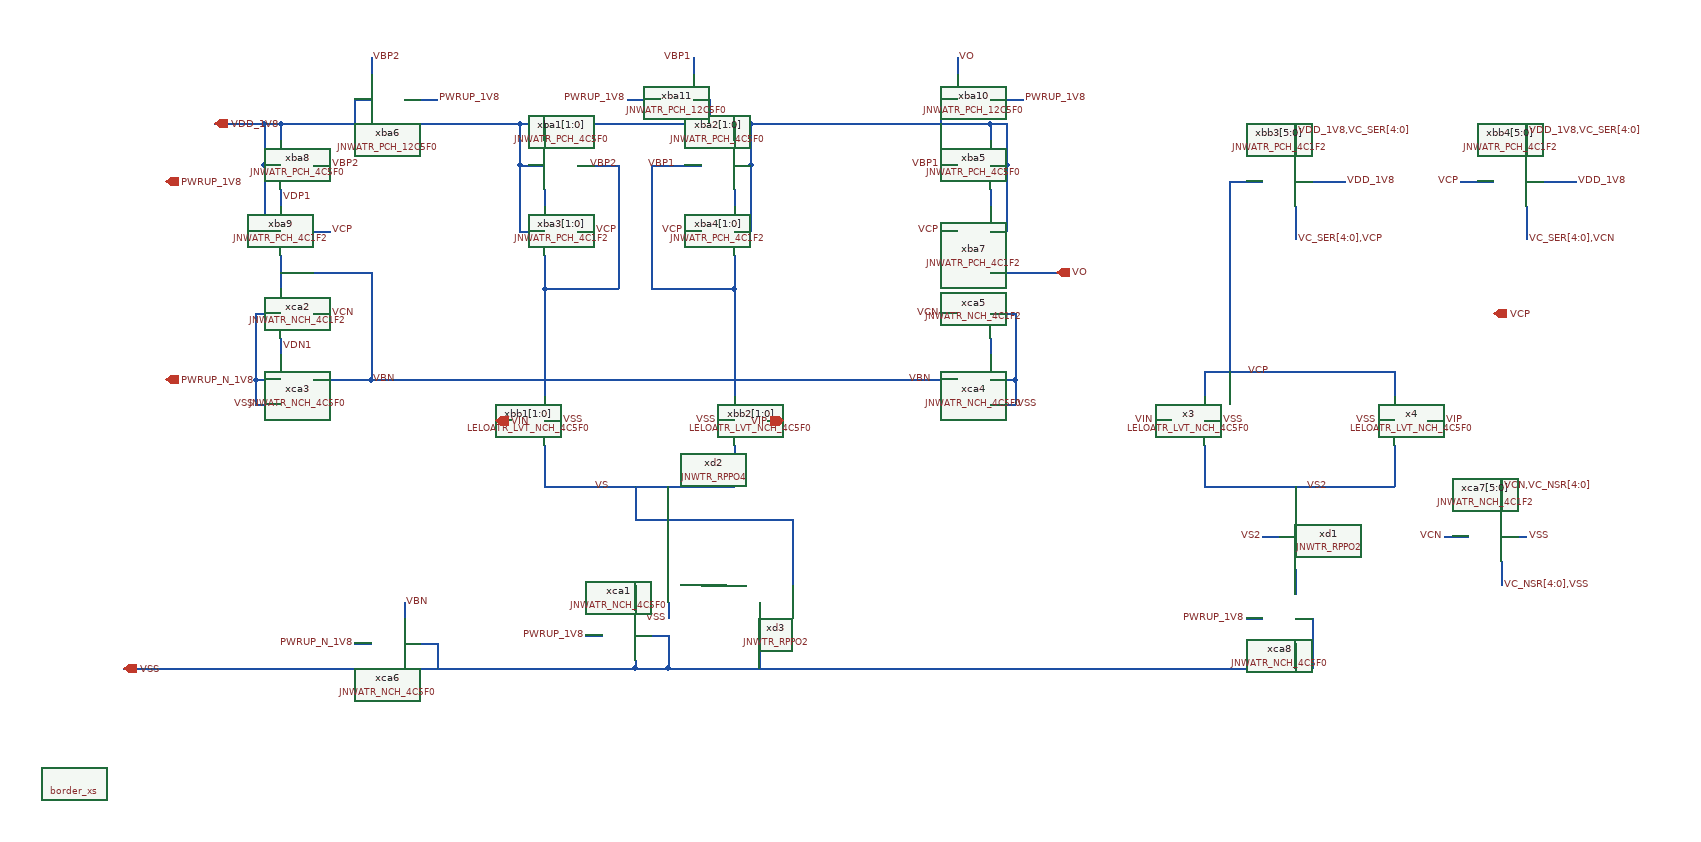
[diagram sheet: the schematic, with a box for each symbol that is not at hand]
v {xschem version=3.4.7 file_version=1.2}
G {}
K {}
V {}
S {}
E {}
N 100 -100 210 -100 {lab=VSS}
N 210 -760 270 -760 {lab=VDD_1V8}
N 610 -370 610 -320 {lab=VS}
N 610 -320 840 -320 {lab=VS}
N 840 -370 840 -320 {lab=VS}
N 760 -180 760 -160 {lab=VSS}
N 720 -320 720 -280 {lab=VS}
N 210 -100 720 -100 {lab=VSS}
N 720 -110 720 -100 {lab=VSS}
N 720 -140 760 -140 {lab=VSS}
N 760 -140 760 -100 {lab=VSS}
N 720 -100 760 -100 {lab=VSS}
N 720 -200 720 -170 {lab=#net1}
N 610 -400 630 -400 {lab=VSS}
N 820 -400 840 -400 {lab=VSS}
N 1410 -370 1410 -320 {lab=VS2}
N 1410 -320 1640 -320 {lab=VS2}
N 1640 -370 1640 -320 {lab=VS2}
N 1410 -400 1430 -400 {lab=VSS}
N 1620 -400 1640 -400 {lab=VSS}
N 580 -710 610 -710 {lab=VDD_1V8}
N 580 -760 580 -710 {lab=VDD_1V8}
N 580 -760 860 -760 {lab=VDD_1V8}
N 860 -760 860 -710 {lab=VDD_1V8}
N 840 -710 860 -710 {lab=VDD_1V8}
N 840 -760 840 -740 {lab=VDD_1V8}
N 610 -760 610 -740 {lab=VDD_1V8}
N 840 -630 860 -630 {lab=VDD_1V8}
N 860 -710 860 -630 {lab=VDD_1V8}
N 840 -680 840 -660 {lab=#net2}
N 650 -710 700 -710 {lab=VBP2}
N 700 -710 700 -560 {lab=VBP2}
N 610 -560 700 -560 {lab=VBP2}
N 610 -590 610 -560 {lab=VBP2}
N 610 -560 610 -430 {lab=VBP2}
N 740 -710 800 -710 {lab=VBP1}
N 740 -710 740 -560 {lab=VBP1}
N 740 -560 840 -560 {lab=VBP1}
N 840 -600 840 -560 {lab=VBP1}
N 610 -600 610 -590 {lab=VBP2}
N 580 -630 610 -630 {lab=VDD_1V8}
N 580 -710 580 -630 {lab=VDD_1V8}
N 840 -560 840 -430 {lab=VBP1}
N 1170 -760 1170 -710 {lab=VDD_1V8}
N 1150 -710 1170 -710 {lab=VDD_1V8}
N 1150 -760 1150 -740 {lab=VDD_1V8}
N 1150 -630 1170 -630 {lab=VDD_1V8}
N 1170 -710 1170 -630 {lab=VDD_1V8}
N 1150 -680 1150 -660 {lab=#net3}
N 1150 -600 1150 -560 {lab=VO}
N 650 -630 670 -630 {lab=VCP}
N 780 -630 800 -630 {lab=VCP}
N 610 -680 610 -660 {lab=#net4}
N 1090 -710 1110 -710 {lab=VBP1}
N 1090 -630 1110 -630 {lab=VCP}
N 860 -760 1150 -760 {lab=VDD_1V8}
N 1150 -760 1170 -760 {lab=VDD_1V8}
N 270 -760 270 -710 {lab=VDD_1V8}
N 270 -710 290 -710 {lab=VDD_1V8}
N 290 -760 290 -740 {lab=VDD_1V8}
N 270 -630 290 -630 {lab=VDD_1V8}
N 270 -710 270 -630 {lab=VDD_1V8}
N 290 -680 290 -660 {lab=VDP1}
N 290 -600 290 -560 {lab=VBN}
N 330 -710 350 -710 {lab=VBP2}
N 330 -630 350 -630 {lab=VCP}
N 290 -760 580 -760 {lab=VDD_1V8}
N 270 -760 290 -760 {lab=VDD_1V8}
N 290 -500 290 -480 {lab=VDN1}
N 260 -530 290 -530 {lab=VSS}
N 260 -530 260 -450 {lab=VSS}
N 260 -450 290 -450 {lab=VSS}
N 260 -450 260 -420 {lab=VSS}
N 260 -420 290 -420 {lab=VSS}
N 330 -530 350 -530 {lab=VCN}
N 330 -450 400 -450 {lab=VBN}
N 400 -580 400 -450 {lab=VBN}
N 290 -580 400 -580 {lab=VBN}
N 1150 -600 1150 -560 {lab=VO}
N 1150 -500 1150 -480 {lab=#net5}
N 1150 -530 1180 -530 {lab=VSS}
N 1180 -530 1180 -450 {lab=VSS}
N 1150 -450 1180 -450 {lab=VSS}
N 1180 -450 1180 -420 {lab=VSS}
N 1150 -420 1180 -420 {lab=VSS}
N 1090 -530 1110 -530 {lab=VCN}
N 1080 -450 1110 -450 {lab=VBN}
N 400 -450 1080 -450 {lab=VBN}
N 1150 -580 1230 -580 {lab=VO}
N 380 -790 400 -790 {lab=VDD_1V8}
N 380 -790 380 -760 {lab=VDD_1V8}
N 400 -840 400 -820 {lab=VBP2}
N 440 -790 480 -790 {lab=PWRUP_1V8}
N 790 -790 810 -790 {lab=VDD_1V8}
N 810 -790 810 -760 {lab=VDD_1V8}
N 790 -840 790 -820 {lab=VBP1}
N 710 -790 750 -790 {lab=PWRUP_1V8}
N 440 -130 480 -130 {lab=VSS}
N 480 -130 480 -100 {lab=VSS}
N 440 -180 440 -160 {lab=VBN}
N 380 -130 400 -130 {lab=PWRUP_N_1V8}
N 1410 -460 1410 -430 {lab=VCP}
N 1410 -460 1640 -460 {lab=VCP}
N 1640 -460 1640 -430 {lab=VCP}
N 880 -400 900 -400 {lab=VIP}
N 550 -400 570 -400 {lab=VIN}
N 1680 -400 1700 -400 {lab=VIP}
N 1350 -400 1370 -400 {lab=VIN}
N 1520 -690 1550 -690 {lab=VDD_1V8}
N 1550 -690 1580 -690 {lab=VDD_1V8}
N 1440 -690 1480 -690 {lab=VCP}
N 1520 -760 1520 -720 {lab=VDD_1V8,VC_SER[4:0]}
N 1520 -660 1520 -620 {lab=VC_SER[4:0],VCP}
N 1800 -690 1830 -690 {lab=VDD_1V8}
N 1830 -690 1860 -690 {lab=VDD_1V8}
N 1720 -690 1760 -690 {lab=VCP}
N 1800 -760 1800 -720 {lab=VDD_1V8,VC_SER[4:0]}
N 1800 -660 1800 -620 {lab=VC_SER[4:0],VCN}
N 1440 -690 1440 -460 {lab=VCP}
N 760 -100 1540 -100 {lab=VSS}
N 1540 -160 1540 -100 {lab=VSS}
N 1520 -160 1540 -160 {lab=VSS}
N 1520 -130 1520 -100 {lab=VSS}
N 1520 -220 1520 -190 {lab=#net6}
N 1480 -260 1500 -260 {lab=VS2}
N 1520 -320 1520 -300 {lab=VS2}
N 1460 -160 1480 -160 {lab=PWRUP_1V8}
N 1770 -330 1770 -290 {lab=VCN,VC_NSR[4:0]}
N 1700 -260 1730 -260 {lab=VCN}
N 1770 -260 1800 -260 {lab=VSS}
N 1770 -230 1770 -200 {lab=VC_NSR[4:0],VSS}
N 1090 -790 1110 -790 {lab=VDD_1V8}
N 1090 -790 1090 -760 {lab=VDD_1V8}
N 1110 -840 1110 -820 {lab=VO}
N 1150 -790 1190 -790 {lab=PWRUP_1V8}
N 660 -140 680 -140 {lab=PWRUP_1V8}
N 870 -180 870 -100 {lab=VSS}
N 800 -200 830 -200 {lab=#net7}
N 910 -280 910 -200 {lab=VS}
N 720 -280 910 -280 {lab=VS}
C {devices/ipin.sym} 210 -760 2 1 {name=p4 lab=VDD_1V8}
C {devices/ipin.sym} 100 -100 2 1 {name=p5 lab=VSS}
C {JNW_ATR_SKY130A/JNWATR_NCH_4C5F0.sym} 330 -450 0 1 {name=xca3}
C {devices/ipin.sym} 150 -450 2 1 {name=p9 lab=PWRUP_N_1V8}
C {devices/ipin.sym} 150 -690 2 1 {name=p10 lab=PWRUP_1V8}
C {cborder/border_xs.sym} 40 40 0 0 {user="Carsten Wulff" company="Carsten Wulff Software"}
C {LELO_ATR_SKY130A/LELOATR_LVT_NCH_4C5F0.sym} 570 -400 0 0 {name=xbb1[1:0]}
C {LELO_ATR_SKY130A/LELOATR_LVT_NCH_4C5F0.sym} 880 -400 0 1 {name=xbb2[1:0]}
C {JNW_TR_SKY130A/JNWTR_RPPO4.sym} 800 -200 0 1 {name=xd2 }
C {devices/lab_wire.sym} 760 -160 3 0 {name=p15 sig_type=std_logic lab=VSS}
C {JNW_ATR_SKY130A/JNWATR_NCH_4C5F0.sym} 680 -140 0 0 {name=xca1}
C {devices/lab_wire.sym} 630 -400 0 1 {name=p1 sig_type=std_logic lab=VSS}
C {devices/lab_wire.sym} 820 -400 0 0 {name=p2 sig_type=std_logic lab=VSS}
C {LELO_ATR_SKY130A/LELOATR_LVT_NCH_4C5F0.sym} 1370 -400 0 0 {name=x3 }
C {LELO_ATR_SKY130A/LELOATR_LVT_NCH_4C5F0.sym} 1680 -400 0 1 {name=x4 }
C {devices/lab_wire.sym} 1430 -400 0 1 {name=p3 sig_type=std_logic lab=VSS}
C {devices/lab_wire.sym} 1620 -400 0 0 {name=p6 sig_type=std_logic lab=VSS}
C {devices/lab_wire.sym} 690 -320 0 0 {name=p7 sig_type=std_logic lab=VS}
C {JNW_ATR_SKY130A/JNWATR_PCH_4C5F0.sym} 650 -710 0 1 {name=xba1[1:0]}
C {JNW_ATR_SKY130A/JNWATR_PCH_4C5F0.sym} 800 -710 0 0 {name=xba2[1:0]}
C {JNW_ATR_SKY130A/JNWATR_PCH_4C1F2.sym} 650 -630 0 1 {name=xba3[1:0]
}
C {JNW_ATR_SKY130A/JNWATR_PCH_4C1F2.sym} 800 -630 0 0 {name=xba4[1:0]}
C {JNW_ATR_SKY130A/JNWATR_PCH_4C5F0.sym} 1110 -710 0 0 {name=xba5}
C {JNW_ATR_SKY130A/JNWATR_PCH_4C1F2.sym} 1110 -630 0 0 {name=xba7}
C {devices/lab_wire.sym} 670 -630 0 1 {name=p8 sig_type=std_logic lab=VCP}
C {devices/lab_wire.sym} 780 -630 0 0 {name=p11 sig_type=std_logic lab=VCP}
C {devices/lab_wire.sym} 770 -710 0 0 {name=p12 sig_type=std_logic lab=VBP1}
C {devices/lab_wire.sym} 700 -710 0 0 {name=p14 sig_type=std_logic lab=VBP2}
C {devices/lab_wire.sym} 1090 -710 0 0 {name=p16 sig_type=std_logic lab=VBP1}
C {devices/lab_wire.sym} 1090 -630 0 0 {name=p17 sig_type=std_logic lab=VCP}
C {JNW_ATR_SKY130A/JNWATR_PCH_4C5F0.sym} 330 -710 0 1 {name=xba8}
C {JNW_ATR_SKY130A/JNWATR_PCH_4C1F2.sym} 330 -630 0 1 {name=xba9}
C {devices/lab_wire.sym} 350 -710 0 1 {name=p18 sig_type=std_logic lab=VBP2
}
C {devices/lab_wire.sym} 350 -630 0 1 {name=p19 sig_type=std_logic lab=VCP}
C {JNW_ATR_SKY130A/JNWATR_NCH_4C1F2.sym} 330 -530 0 1 {name=xca2}
C {devices/lab_wire.sym} 350 -530 0 1 {name=p13 sig_type=std_logic lab=VCN}
C {devices/lab_wire.sym} 400 -450 0 1 {name=p20 sig_type=std_logic lab=VBN}
C {devices/lab_wire.sym} 260 -420 0 0 {name=p21 sig_type=std_logic lab=VSS}
C {JNW_ATR_SKY130A/JNWATR_NCH_4C5F0.sym} 1110 -450 0 0 {name=xca4}
C {JNW_ATR_SKY130A/JNWATR_NCH_4C1F2.sym} 1110 -530 0 0 {name=xca5}
C {devices/lab_wire.sym} 1090 -530 0 0 {name=p22 sig_type=std_logic lab=VCN}
C {devices/lab_wire.sym} 1180 -420 0 1 {name=p23 sig_type=std_logic lab=VSS}
C {devices/lab_wire.sym} 1080 -450 0 0 {name=p24 sig_type=std_logic lab=VBN}
C {devices/opin.sym} 1230 -580 0 0 {name=p25 lab=VO}
C {JNW_ATR_SKY130A/JNWATR_PCH_12C5F0.sym} 440 -790 2 0 {name=xba6}
C {devices/lab_wire.sym} 480 -790 0 1 {name=p26 sig_type=std_logic lab=PWRUP_1V8
}
C {devices/lab_wire.sym} 400 -840 0 1 {name=p27 sig_type=std_logic lab=VBP2
}
C {JNW_ATR_SKY130A/JNWATR_PCH_12C5F0.sym} 750 -790 2 1 {name=xba11}
C {devices/lab_wire.sym} 710 -790 0 0 {name=p28 sig_type=std_logic lab=PWRUP_1V8
}
C {devices/lab_wire.sym} 790 -840 0 0 {name=p29 sig_type=std_logic lab=VBP1
}
C {JNW_ATR_SKY130A/JNWATR_NCH_4C5F0.sym} 400 -130 0 0 {name=xca6}
C {devices/lab_wire.sym} 380 -130 0 0 {name=p30 sig_type=std_logic lab=PWRUP_N_1V8}
C {devices/lab_wire.sym} 440 -180 0 1 {name=p31 sig_type=std_logic lab=VBN}
C {devices/lab_wire.sym} 1560 -320 0 0 {name=p32 sig_type=std_logic lab=VS2}
C {devices/ipin.sym} 900 -400 2 0 {name=p33 lab=VIP}
C {devices/ipin.sym} 550 -400 2 1 {name=p34 lab=VIN}
C {JNW_ATR_SKY130A/JNWATR_PCH_4C1F2.sym} 1480 -690 0 0 {name=xbb3[5:0]}
C {devices/lab_wire.sym} 1580 -690 0 1 {name=p40 sig_type=std_logic lab=VDD_1V8}
C {devices/lab_wire.sym} 1520 -750 0 1 {name=p41 sig_type=std_logic lab=VDD_1V8,VC_SER[4:0]}
C {devices/lab_wire.sym} 1520 -620 0 1 {name=p42 sig_type=std_logic lab=VC_SER[4:0],VCP}
C {JNW_ATR_SKY130A/JNWATR_PCH_4C1F2.sym} 1760 -690 0 0 {name=xbb4[5:0]}
C {devices/lab_wire.sym} 1860 -690 0 1 {name=p43 sig_type=std_logic lab=VDD_1V8}
C {devices/lab_wire.sym} 1800 -750 0 1 {name=p44 sig_type=std_logic lab=VDD_1V8,VC_SER[4:0]}
C {devices/lab_wire.sym} 1800 -620 0 1 {name=p45 sig_type=std_logic lab=VC_SER[4:0],VCN}
C {devices/lab_wire.sym} 1490 -460 0 0 {name=p37 sig_type=std_logic lab=VCP}
C {JNW_ATR_SKY130A/JNWATR_NCH_4C1F2.sym} 1730 -260 0 0 {name=xca7[5:0]}
C {JNW_TR_SKY130A/JNWTR_RPPO2.sym} 1520 -220 1 1 {name=xd1 }
C {JNW_ATR_SKY130A/JNWATR_NCH_4C5F0.sym} 1480 -160 0 0 {name=xca8}
C {devices/lab_wire.sym} 1480 -260 0 0 {name=p38 sig_type=std_logic lab=VS2}
C {devices/lab_wire.sym} 1460 -160 0 0 {name=p39 sig_type=std_logic lab=PWRUP_1V8}
C {devices/lab_wire.sym} 1700 -260 0 0 {name=p46 sig_type=std_logic lab=VCN}
C {devices/lab_wire.sym} 1800 -260 0 1 {name=p47 sig_type=std_logic lab=VSS}
C {devices/lab_wire.sym} 1770 -320 0 1 {name=p48 sig_type=std_logic lab=VCN,VC_NSR[4:0]}
C {devices/lab_wire.sym} 1770 -200 0 1 {name=p49 sig_type=std_logic lab=VC_NSR[4:0],VSS}
C {JNW_ATR_SKY130A/JNWATR_PCH_12C5F0.sym} 1150 -790 2 0 {name=xba10}
C {devices/lab_wire.sym} 1190 -790 0 1 {name=p50 sig_type=std_logic lab=PWRUP_1V8
}
C {devices/lab_wire.sym} 1110 -840 0 1 {name=p51 sig_type=std_logic lab=VO
}
C {devices/lab_wire.sym} 660 -140 0 0 {name=p52 sig_type=std_logic lab=PWRUP_1V8}
C {devices/opin.sym} 1760 -530 0 0 {name=p53 lab=VCP}
C {devices/lab_wire.sym} 1700 -400 0 1 {name=p35 sig_type=std_logic lab=VIP}
C {devices/lab_wire.sym} 1350 -400 0 0 {name=p36 sig_type=std_logic lab=VIN}
C {devices/lab_wire.sym} 1720 -690 0 0 {name=p54 sig_type=std_logic lab=VCP}
C {devices/lab_wire.sym} 290 -670 0 1 {name=p55 sig_type=std_logic lab=VDP1}
C {devices/lab_wire.sym} 290 -490 0 1 {name=p56 sig_type=std_logic lab=VDN1}
C {JNW_TR_SKY130A/JNWTR_RPPO2.sym} 910 -200 0 1 {name=xd3 }
